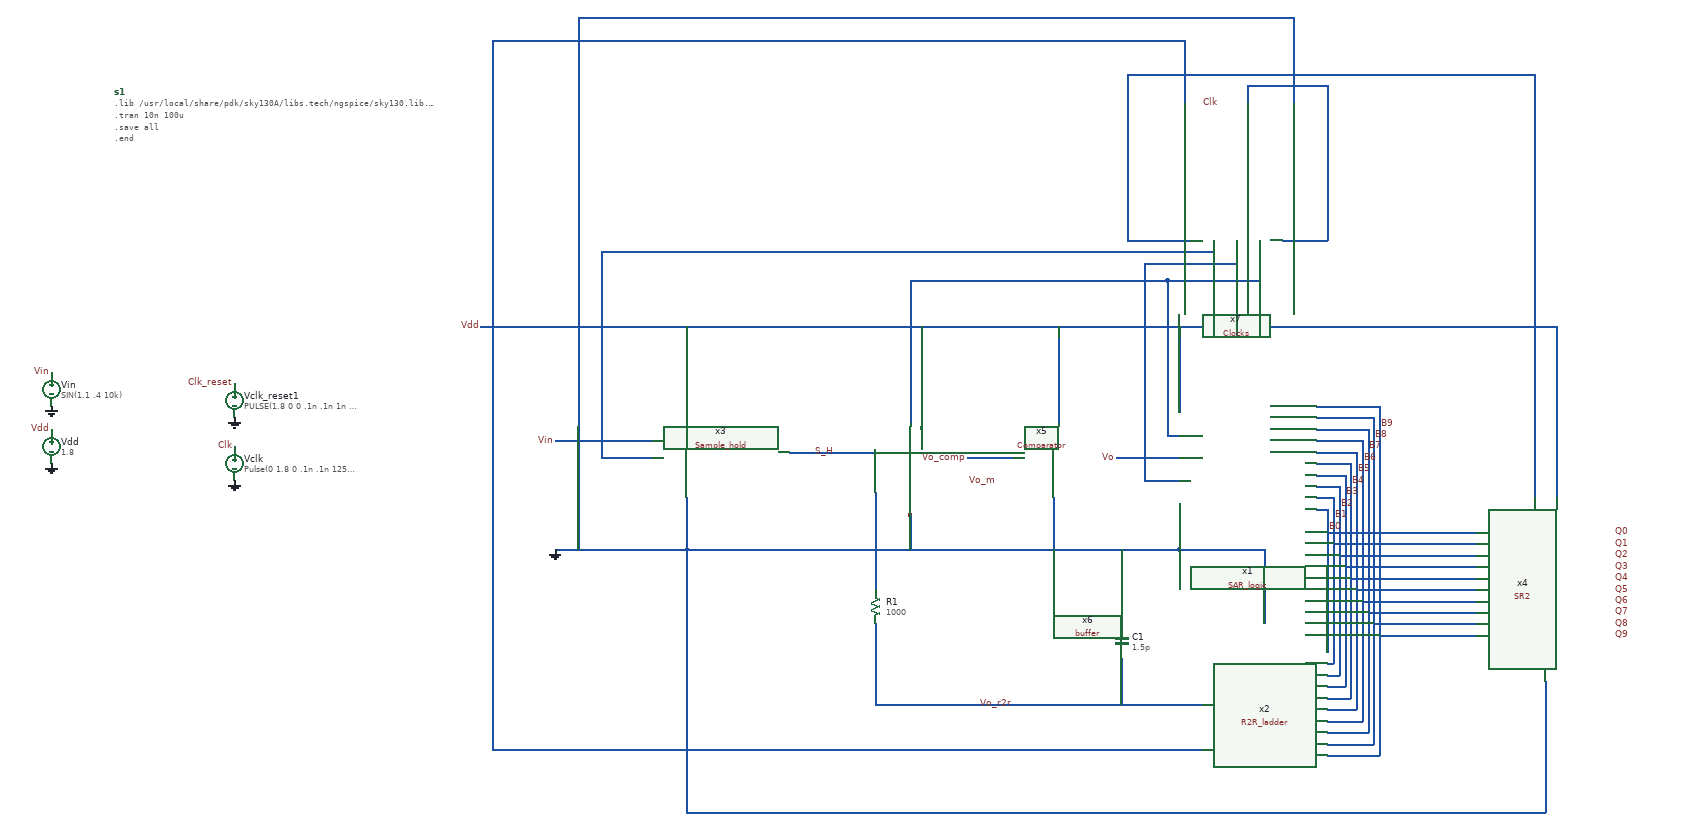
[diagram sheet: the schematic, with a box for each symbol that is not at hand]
v {xschem version=3.4.8RC file_version=1.3}
G {}
K {}
V {}
S {}
F {}
E {}
B 5 -122.5 47.5 -117.5 52.5 {name=GND dir=in}
N 610 40 610 290 {lab=B0}
N 590 40 610 40 {lab=B0}
N 590 20 620 20 {lab=B1}
N 620 20 620 310 {lab=B1}
N 610 310 620 310 {lab=B1}
N 590 0 630 0 {lab=B2}
N 630 0 630 330 {lab=B2}
N 610 330 630 330 {lab=B2}
N 590 -20 640 -20 {lab=B3}
N 640 -20 640 350 {lab=B3}
N 610 350 640 350 {lab=B3}
N 590 -40 650 -40 {lab=B4}
N 650 -40 650 370 {lab=B4}
N 610 370 650 370 {lab=B4}
N 590 -60 660 -60 {lab=B5}
N 660 -60 660 390 {lab=B5}
N 610 390 660 390 {lab=B5}
N 590 -80 670 -80 {lab=B6}
N 670 -80 670 410 {lab=B6}
N 610 410 670 410 {lab=B6}
N 590 -100 680 -100 {lab=B7}
N 680 -100 680 430 {lab=B7}
N 610 430 680 430 {lab=B7}
N 590 -120 690 -120 {lab=B8}
N 690 -120 690 450 {lab=B8}
N 610 450 690 450 {lab=B8}
N 590 -140 700 -140 {lab=B9}
N 700 -140 700 470 {lab=B9}
N 610 470 700 470 {lab=B9}
N -180 380 350 380 {lab=Vo_r2r}
N 350 30 350 110 {lab=0}
N -510 110 350 110 {lab=0}
N -510 20 -510 110 {lab=0}
N -120 50 -120 110 {lab=0}
N 350 110 480 110 {lab=0}
N 480 110 490 110 {lab=0}
N -740 -80 -570 -80 {lab=Vin}
N 610 80 870 80 {lab=B0}
N 620 100 870 100 {lab=B1}
N 630 120 870 120 {lab=B2}
N 640 140 870 140 {lab=B3}
N 650 160 870 160 {lab=B4}
N 660 180 870 180 {lab=B5}
N 670 200 870 200 {lab=B6}
N 680 220 870 220 {lab=B7}
N 690 240 870 240 {lab=B8}
N 700 260 870 260 {lab=B9}
N 980 570 990 570 {lab=0}
N 990 340 990 570 {lab=0}
N -510 110 -510 550 {lab=0}
N -510 570 980 570 {lab=0}
N -510 550 -510 570 {lab=0}
N -740 110 -510 110 {lab=0}
N 1010 -280 1010 20 {lab=Vdd}
N -730 -280 1010 -280 {lab=Vdd}
N -740 -280 -730 -280 {lab=Vdd}
N -510 -280 -510 -140 {lab=Vdd}
N 350 -280 350 -130 {lab=Vdd}
N -330 -60 -180 -60 {lab=S_H}
N -100 -280 -100 -100 {lab=Vdd}
N 260 -50 350 -50 {lab=Vo}
N -180 10 -180 180 {lab=#net1}
N -180 240 -180 380 {lab=Vo_r2r}
N 350 380 390 380 {lab=Vo_r2r}
N 490 110 500 110 {lab=0}
N 500 110 500 240 {lab=0}
N -870 -280 -750 -280 {lab=Vdd}
N -750 -280 -740 -280 {lab=Vdd}
N -850 460 390 460 {lab=Vdd}
N -850 -280 -850 460 {lab=Vdd}
N 250 110 250 240 {lab=0}
N 250 300 250 380 {lab=Vo_r2r}
N -20 -50 60 -50 {lab=Vo_comp}
N 240 -50 260 -50 {lab=Vo}
N 140 -280 140 -110 {lab=Vdd}
N 130 20 130 110 {lab=0}
N 290 -10 350 -10 {lab=#net2}
N 290 -390 290 -10 {lab=#net2}
N 290 -390 450 -390 {lab=#net2}
N 450 -430 450 -390 {lab=#net2}
N 490 -430 490 -360 {lab=#net3}
N 330 -360 490 -360 {lab=#net3}
N 330 -360 330 -90 {lab=#net3}
N 330 -90 350 -90 {lab=#net3}
N 410 -430 410 -410 {lab=#net4}
N -660 -50 -570 -50 {lab=#net4}
N -660 -410 410 -410 {lab=#net4}
N -660 -410 -660 -50 {lab=#net4}
N 260 -430 370 -430 {lab=#net5}
N 260 -720 260 -430 {lab=#net5}
N 970 -720 970 20 {lab=#net5}
N 260 -720 970 -720 {lab=#net5}
N -120 -360 330 -360 {lab=#net3}
N -120 -360 -120 -120 {lab=#net3}
N -120 -120 -120 -110 {lab=#net3}
N 530 -430 610 -430 {lab=#net6}
N 610 -700 610 -430 {lab=#net6}
N 470 -700 610 -700 {lab=#net6}
N 470 -700 470 -670 {lab=#net6}
N -700 -820 -700 110 {lab=0}
N -700 -820 550 -820 {lab=0}
N 550 -820 550 -670 {lab=0}
N -850 -780 -850 -280 {lab=Vdd}
N -850 -780 350 -780 {lab=Vdd}
N 350 -780 360 -780 {lab=Vdd}
N 360 -780 360 -670 {lab=Vdd}
C {/home/jetha/Projects/sky130/SAR_ADC/SAR/SAR_logic.sym} 490 260 0 0 {name=x1}
C {/home/jetha/Projects/sky130/SAR_ADC/R2R_Ladder/R2R_ladder.sym} 500 380 0 0 {name=x2}
C {/home/jetha/Projects/sky130/SAR_ADC/S&H/Sample_hold.sym} -450 -60 0 0 {name=x3}
C {lab_pin.sym} -740 -80 0 0 {name=p1 sig_type=std_logic lab=Vin}
C {/home/jetha/Projects/sky130/SAR_ADC/Shift_register/SR2.sym} 990 170 0 0 {name=x4}
C {gnd.sym} -740 110 0 0 {name=l1 lab=0}
C {lab_pin.sym} -870 -280 0 0 {name=p6 sig_type=std_logic lab=Vdd}
C {/home/jetha/Projects/sky130/SAR_ADC/Comparator/Comparator.sym} -100 -10 0 0 {name=x5}
C {code_shown.sym} -1510 -690 0 0 {name=s1 only_toplevel=false value="
.lib /usr/local/share/pdk/sky130A/libs.tech/ngspice/sky130.lib.spice tt 

.tran 10n 100u
.save all
.end
"}
C {lab_pin.sym} 1110 80 2 0 {name=p11 sig_type=std_logic lab=Q0}
C {lab_pin.sym} 1110 100 2 0 {name=p12 sig_type=std_logic lab=Q1}
C {lab_pin.sym} 1110 120 2 0 {name=p13 sig_type=std_logic lab=Q2}
C {lab_pin.sym} 1110 140 2 0 {name=p14 sig_type=std_logic lab=Q3}
C {lab_pin.sym} 1110 160 2 0 {name=p15 sig_type=std_logic lab=Q4}
C {lab_pin.sym} 1110 180 2 0 {name=p16 sig_type=std_logic lab=Q5}
C {lab_pin.sym} 1110 200 2 0 {name=p17 sig_type=std_logic lab=Q6}
C {lab_pin.sym} 1110 220 2 0 {name=p18 sig_type=std_logic lab=Q7}
C {lab_pin.sym} 1110 240 2 0 {name=p19 sig_type=std_logic lab=Q8}
C {lab_pin.sym} 1110 260 2 0 {name=p20 sig_type=std_logic lab=Q9}
C {vsource.sym} -1620 -170 0 0 {name=Vin value="SIN(1.1 .4 10k)" savecurrent=false}
C {lab_pin.sym} -1620 -200 0 0 {name=p21 sig_type=std_logic lab=Vin}
C {gnd.sym} -1620 -140 0 0 {name=l5 lab=0}
C {vsource.sym} -1620 -70 0 0 {name=Vdd value=1.8 savecurrent=false}
C {gnd.sym} -1620 -40 0 0 {name=Vdd2 lab=0
value=1.8}
C {lab_pin.sym} -1620 -100 0 0 {name=p22 sig_type=std_logic lab=Vdd}
C {lab_pin.sym} -250 -60 1 0 {name=p24 sig_type=std_logic lab=S_H}
C {lab_pin.sym} 60 380 1 0 {name=p26 sig_type=std_logic lab=Vo_r2r}
C {lab_pin.sym} 610 70 2 0 {name=p27 sig_type=std_logic lab=B0}
C {lab_pin.sym} 620 50 2 0 {name=p28 sig_type=std_logic lab=B1}
C {lab_pin.sym} 630 30 2 0 {name=p29 sig_type=std_logic lab=B2}
C {lab_pin.sym} 640 10 2 0 {name=p30 sig_type=std_logic lab=B3}
C {lab_pin.sym} 650 -10 2 0 {name=p31 sig_type=std_logic lab=B4}
C {lab_pin.sym} 660 -30 2 0 {name=p32 sig_type=std_logic lab=B5}
C {lab_pin.sym} 670 -50 2 0 {name=p33 sig_type=std_logic lab=B6}
C {lab_pin.sym} 680 -70 2 0 {name=p34 sig_type=std_logic lab=B7}
C {lab_pin.sym} 690 -90 2 0 {name=p35 sig_type=std_logic lab=B8}
C {lab_pin.sym} 700 -110 2 0 {name=p36 sig_type=std_logic lab=B9}
C {lab_pin.sym} -20 -10 2 0 {name=p37 sig_type=std_logic lab=Vo_m}
C {lab_pin.sym} 240 -50 1 0 {name=p38 sig_type=std_logic lab=Vo}
C {res.sym} -180 210 0 0 {name=R1
value=1000
footprint=1206
device=resistor
m=1}
C {capa.sym} 250 270 0 0 {name=C1
m=1
value=1.5p
footprint=1206
device="ceramic capacitor"}
C {lab_pin.sym} -20 -50 1 0 {name=p39 sig_type=std_logic lab=Vo_comp}
C {buffer.sym} 100 260 0 0 {name=x6}
C {Clocks.sym} 430 -350 0 0 {name=x7}
C {vsource.sym} -1300 -40 0 0 {name=Vclk value="Pulse(0 1.8 0 .1n .1n 125n 250n)" savecurrent=false}
C {gnd.sym} -1300 -10 0 0 {name=l7 lab=0}
C {lab_pin.sym} -1300 -70 0 0 {name=p9 sig_type=std_logic lab=Clk}
C {vsource.sym} -1300 -150 0 0 {name=Vclk_reset1 value="PULSE(1.8 0 0 .1n .1n 1n 200u)" savecurrent=false}
C {gnd.sym} -1300 -120 0 0 {name=l8 lab=0}
C {lab_pin.sym} -1300 -180 0 0 {name=p2 sig_type=std_logic lab=Clk_reset}
C {lab_pin.sym} 420 -670 0 0 {name=p3 sig_type=std_logic lab=Clk}
